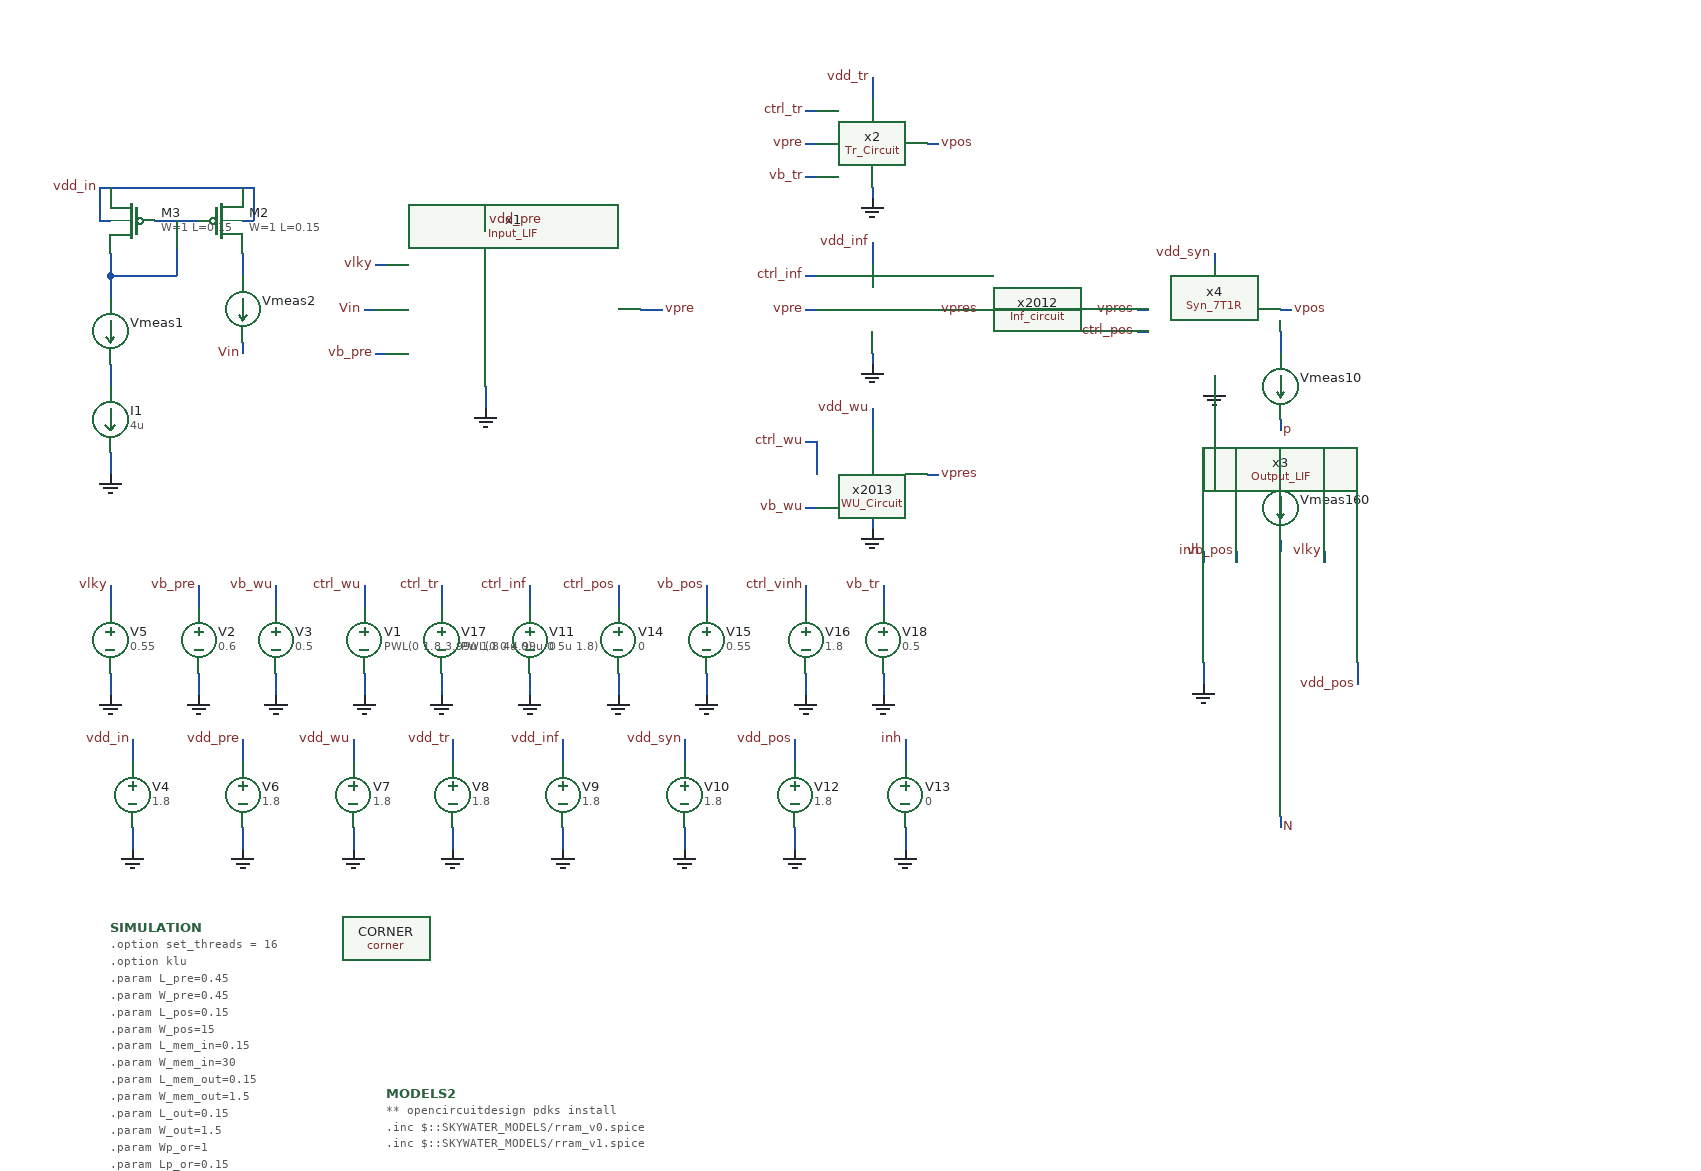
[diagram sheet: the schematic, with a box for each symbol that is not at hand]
v {xschem version=3.4.5 file_version=1.2
}
G {}
K {}
V {}
S {}
E {}
B 2 -1600 -1600 -800 -1200 {flags=graph
y1=-8e-07
y2=3.2e-06
ypos1=0
ypos2=2
divy=5
subdivy=1
unity=1
x1=0
x2=7e-05
divx=5
subdivx=1
xlabmag=1.0
ylabmag=1.0


dataset=-1
unitx=1
logx=0
logy=0



color=4
node=i(Vmeas1)}
B 2 -1600 -1200 -800 -800 {flags=graph
y1=0.34
y2=1.9
ypos1=0
ypos2=2
divy=5
subdivy=1
unity=1
x1=0
x2=7e-05
divx=5
subdivx=1
xlabmag=1.0
ylabmag=1.0


dataset=-1
unitx=1
logx=0
logy=0
color=4
node=vpre}
B 2 -800 -1200 0 -800 {flags=graph
y1=0
y2=1.8
ypos1=0
ypos2=2
divy=5
subdivy=1
unity=1
x1=0
x2=7e-05
divx=5
subdivx=1
xlabmag=1.0
ylabmag=1.0


dataset=-1
unitx=1
logx=0
logy=0



color=4
node=ctrl_wu}
B 2 -800 -1600 0 -1200 {flags=graph
y1=-4.1e-05
y2=0.00032
ypos1=0
ypos2=2
divy=5
subdivy=1
unity=1
x1=0
x2=7e-05
divx=5
subdivx=1
xlabmag=1.0
ylabmag=1.0


dataset=-1
unitx=1
logx=0
logy=0







color=17
node="\\"-1.8 i(v10) *\\""}
B 2 -1600 -800 -800 -400 {flags=graph
y1=1.1
y2=5.3
ypos1=0
ypos2=2
divy=5
subdivy=1
unity=1
x1=0
x2=7e-05
divx=5
subdivx=1
xlabmag=1.0
ylabmag=1.0


dataset=-1
unitx=1
logx=0
logy=0

color=6
node="\\"S20; 5 n.x4.xr1.n1#ngap -\\""}
B 2 -800 -800 0 -400 {flags=graph
y1=0
y2=1.8
ypos1=0
ypos2=2
divy=5
subdivy=1
unity=1
x1=0
x2=7e-05
divx=5
subdivx=1
xlabmag=1.0
ylabmag=1.0


dataset=-1
unitx=1
logx=0
logy=0



color="4 6 7"
node="ctrl_inf
ctrl_tr
ctrl_wu"}
B 2 -1600 -400 -800 0 {flags=graph
y1=0
y2=0.01
ypos1=0
ypos2=2
divy=5
subdivy=1
unity=1
x1=0
x2=7e-05
divx=5
subdivx=1
xlabmag=1.0
ylabmag=1.0


dataset=-1
unitx=1
logx=0
logy=0

color=6
node=\\"i(Vmeas10)\\"}
B 2 -800 -400 0 0 {flags=graph
y1=-0.42215
y2=1.75283
ypos1=0
ypos2=2
divy=5
subdivy=1
unity=1
x1=0
x2=7e-05
divx=5
subdivx=1
xlabmag=1.0
ylabmag=1.0


dataset=-1
unitx=1
logx=0
logy=0

color="6 4"
node="\\"p0\\"
\\"N0\\""}
N -2320 -1060 -2300 -1060 {
lab=vpre}
N -2720 -810 -2720 -790 {
lab=vb_pre}
N -2720 -730 -2720 -710 {
lab=GND}
N -2800 -930 -2800 -910 {
lab=GND}
N -2680 -1110 -2680 -1090 {
lab=#net1}
N -2680 -1140 -2670 -1140 {
lab=vdd_in}
N -2670 -1170 -2670 -1140 {
lab=vdd_in}
N -2680 -1170 -2670 -1170 {
lab=vdd_in}
N -2760 -1140 -2720 -1140 {
lab=#net2}
N -2800 -1170 -2680 -1170 {
lab=vdd_in}
N -2810 -1140 -2800 -1140 {
lab=vdd_in}
N -2810 -1170 -2810 -1140 {
lab=vdd_in}
N -2810 -1170 -2800 -1170 {
lab=vdd_in}
N -2800 -1110 -2800 -1090 {
lab=#net2}
N -2800 -1090 -2740 -1090 {
lab=#net2}
N -2740 -1140 -2740 -1090 {
lab=#net2}
N -2800 -1010 -2800 -990 {
lab=#net3}
N -2800 -1090 -2800 -1070 {
lab=#net2}
N -2780 -670 -2780 -650 {
lab=vdd_in}
N -2780 -590 -2780 -570 {
lab=GND}
N -2460 -990 -2460 -970 {
lab=GND}
N -2560 -1020 -2550 -1020 {
lab=vb_pre}
N -2680 -1030 -2680 -1020 {
lab=Vin}
N -2570 -1060 -2560 -1060 {
lab=Vin}
N -2560 -1100 -2550 -1100 {
lab=vlky}
N -2800 -810 -2800 -790 {
lab=vlky}
N -2800 -730 -2800 -710 {
lab=GND}
N -2460 -1140 -2460 -1130 {
lab=vdd_pre}
N -1800 -1000 -1800 -990 {
lab=GND}
N -1800 -1110 -1800 -1100 {
lab=vdd_syn}
N -1870 -1060 -1860 -1060 {
lab=vpres}
N -1740 -1060 -1730 -1060 {
lab=vpos}
N -2110 -870 -2110 -860 {
lab=GND}
N -2060 -910 -2050 -910 {
lab=vpres}
N -2110 -1020 -2110 -1010 {
lab=GND}
N -2060 -1060 -2050 -1060 {
lab=vpres}
N -2170 -880 -2160 -880 {
lab=vb_wu}
N -1740 -1040 -1740 -1020 {
lab=#net4}
N -1740 -960 -1740 -950 {
lab=p}
N -2170 -1090 -2160 -1090 {
lab=ctrl_inf}
N -2110 -970 -2110 -950 {
lab=vdd_wu}
N -2110 -1120 -2110 -1100 {
lab=vdd_inf}
N -2170 -940 -2160 -940 {
lab=ctrl_wu}
N -2160 -940 -2160 -910 {
lab=ctrl_wu}
N -2170 -1060 -2160 -1060 {
lab=vpre}
N -2680 -670 -2680 -650 {
lab=vdd_pre}
N -2680 -590 -2680 -570 {
lab=GND}
N -2580 -670 -2580 -650 {
lab=vdd_wu}
N -2580 -590 -2580 -570 {
lab=GND}
N -2490 -670 -2490 -650 {
lab=vdd_tr}
N -2490 -590 -2490 -570 {
lab=GND}
N -2390 -670 -2390 -650 {
lab=vdd_inf}
N -2390 -590 -2390 -570 {
lab=GND}
N -2280 -670 -2280 -650 {
lab=vdd_syn}
N -2280 -590 -2280 -570 {
lab=GND}
N -2570 -810 -2570 -790 {
lab=ctrl_wu}
N -2570 -730 -2570 -710 {
lab=GND}
N -2650 -810 -2650 -790 {
lab=vb_wu}
N -2650 -730 -2650 -710 {
lab=GND}
N -2420 -810 -2420 -790 {
lab=ctrl_inf}
N -2420 -730 -2420 -710 {
lab=GND}
N -1740 -850 -1740 -840 {
lab=#net5}
N -1740 -920 -1740 -910 {
lab=p1}
N -1740 -600 -1740 -590 {
lab=N}
N -1810 -740 -1810 -720 {
lab=GND}
N -1670 -740 -1670 -720 {
lab=vdd_pos}
N -1810 -840 -1810 -830 {
lab=inh}
N -1780 -840 -1780 -830 {
lab=vb_pos}
N -1700 -840 -1700 -830 {
lab=vlky}
N -2180 -670 -2180 -650 {
lab=vdd_pos}
N -2180 -590 -2180 -570 {
lab=GND}
N -2080 -670 -2080 -650 {
lab=inh}
N -2080 -590 -2080 -570 {
lab=GND}
N -2340 -810 -2340 -790 {
lab=ctrl_pos}
N -2340 -730 -2340 -710 {
lab=GND}
N -2260 -810 -2260 -790 {
lab=vb_pos}
N -2260 -730 -2260 -710 {
lab=GND}
N -2170 -810 -2170 -790 {
lab=ctrl_vinh}
N -2170 -730 -2170 -710 {
lab=GND}
N -2110 -1170 -2110 -1160 {
lab=GND}
N -2060 -1210 -2050 -1210 {
lab=vpos}
N -2170 -1180 -2160 -1180 {
lab=vb_tr}
N -2110 -1270 -2110 -1250 {
lab=vdd_tr}
N -2170 -1240 -2160 -1240 {
lab=ctrl_tr}
N -2170 -1210 -2160 -1210 {
lab=vpre}
N -2500 -810 -2500 -790 {
lab=ctrl_tr}
N -2500 -730 -2500 -710 {
lab=GND}
N -2100 -810 -2100 -790 {
lab=vb_tr}
N -2100 -730 -2100 -710 {
lab=GND}
N -1870 -1040 -1860 -1040 {
lab=ctrl_pos}
C {devices/gnd.sym} -2460 -970 0 0 {name=l1 lab=GND}
C {devices/lab_pin.sym} -2560 -1020 0 0 {name=p3 sig_type=std_logic lab=vb_pre}
C {devices/lab_pin.sym} -2300 -1060 2 0 {name=p5 sig_type=std_logic lab=vpre}
C {devices/vsource.sym} -2720 -760 0 0 {name=V2 value=0.6 savecurrent=false}
C {devices/lab_pin.sym} -2720 -810 0 0 {name=p6 sig_type=std_logic lab=vb_pre}
C {devices/gnd.sym} -2720 -710 0 0 {name=l4 lab=GND}
C {devices/code_shown.sym} -2800 -500 0 0 {name=SIMULATION
only_toplevel=true
value="
.option set_threads = 16
.option klu
.param L_pre=0.45
.param W_pre=0.45
.param L_pos=0.15
.param W_pos=15
.param L_mem_in=0.15
.param W_mem_in=30
.param L_mem_out=0.15
.param W_mem_out=1.5
.param L_out=0.15
.param W_out=1.5
.param Wp_or=1
.param Lp_or=0.15
.param Wn_or=1
.param Ln_or=0.15
.param Wp_or_inv=1
.param Lp_or_inv=0.15
.param Wn_or_inv=1
.param Ln_or_inv=0.15
.control
	set wr_vecnames
	set wr_singlescale
	let mc_runs = 150
	let run = 1
	dowhile run <= mc_runs
		tran 1n 70u 0
		*write Syn7T1R_MC\{$&run\}.raw
		wrdata Syn7T1R_MC\{$&run\}.txt v(n.x4.xr1.n1#ngap) i(v10)
		reset
		let run = run + 1
	end
.endc
.save all
" }
C {sky130_fd_pr/corner.sym} -2550 -490 0 0 {name=CORNER only_toplevel=true corner=tt_mm}
C {devices/isource.sym} -2800 -960 0 1 {name=I1 value=4u

}
C {devices/gnd.sym} -2800 -910 0 0 {name=l20 lab=GND}
C {sky130_fd_pr/pfet_01v8.sym} -2700 -1140 0 0 {name=M2
L=0.15
W=1
nf=1
mult=1
ad="'int((nf+1)/2) * W/nf * 0.29'" 
pd="'2*int((nf+1)/2) * (W/nf + 0.29)'"
as="'int((nf+2)/2) * W/nf * 0.29'" 
ps="'2*int((nf+2)/2) * (W/nf + 0.29)'"
nrd="'0.29 / W'" nrs="'0.29 / W'"
sa=0 sb=0 sd=0
model=pfet_01v8
spiceprefix=X
}
C {sky130_fd_pr/pfet_01v8.sym} -2780 -1140 0 1 {name=M3
L=0.15
W=1
nf=1
mult=1
ad="'int((nf+1)/2) * W/nf * 0.29'" 
pd="'2*int((nf+1)/2) * (W/nf + 0.29)'"
as="'int((nf+2)/2) * W/nf * 0.29'" 
ps="'2*int((nf+2)/2) * (W/nf + 0.29)'"
nrd="'0.29 / W'" nrs="'0.29 / W'"
sa=0 sb=0 sd=0
model=pfet_01v8
spiceprefix=X
}
C {devices/lab_pin.sym} -2680 -1020 0 0 {name=p10 sig_type=std_logic lab=Vin}
C {devices/ammeter.sym} -2800 -1040 0 0 {name=Vmeas1 savecurrent=true}
C {devices/ammeter.sym} -2680 -1060 0 0 {name=Vmeas2 savecurrent=true}
C {devices/vsource.sym} -2780 -620 0 0 {name=V4 savecurrent=false value=1.8
*"PWL(0 0 39.9u 0 40u 1.8)"}
C {devices/lab_pin.sym} -2780 -670 0 0 {name=p1 sig_type=std_logic lab=vdd_in}
C {devices/gnd.sym} -2780 -570 0 0 {name=l6 lab=GND}
C {devices/lab_pin.sym} -2570 -1060 0 0 {name=p8 sig_type=std_logic lab=Vin}
C {devices/lab_pin.sym} -2560 -1100 0 0 {name=p11 sig_type=std_logic lab=vlky}
C {devices/vsource.sym} -2800 -760 0 0 {name=V5 savecurrent=false value=0.55}
C {devices/lab_pin.sym} -2800 -810 0 0 {name=p13 sig_type=std_logic lab=vlky}
C {devices/gnd.sym} -2800 -710 0 0 {name=l9 lab=GND}
C {devices/launcher.sym} -1680 -1240 0 0 {name=h5
descr="load waves" 
tclcommand="xschem raw_read $netlist_dir/Syn7T1R_MC2.raw tran"
}
C {/home/ricardo/RATT_repos/Proyectos_xschem/SNN/Input_LIF.sym} -2460 -1060 0 0 {name=x1}
C {devices/lab_pin.sym} -2050 -1210 2 0 {name=p162 sig_type=std_logic lab=vpos}
C {devices/gnd.sym} -1800 -990 0 0 {name=l39 lab=GND}
C {devices/lab_pin.sym} -1870 -1060 0 0 {name=p26 sig_type=std_logic lab=vpres}
C {devices/ammeter.sym} -1740 -990 0 0 {name=Vmeas10 savecurrent=true}
C {devices/lab_pin.sym} -1740 -950 2 0 {name=p46 sig_type=std_logic lab=p}
C {devices/lab_pin.sym} -2050 -910 2 0 {name=p35 sig_type=std_logic lab=vpres}
C {devices/gnd.sym} -2110 -860 0 0 {name=l18 lab=GND}
C {devices/lab_pin.sym} -2170 -1060 0 0 {name=p41 sig_type=std_logic lab=vpre}
C {devices/lab_pin.sym} -2170 -1090 0 0 {name=p42 sig_type=std_logic lab=ctrl_inf}
C {devices/gnd.sym} -2110 -1010 0 0 {name=l10 lab=GND}
C {devices/lab_pin.sym} -2110 -970 0 0 {name=p47 sig_type=std_logic lab=vdd_wu}
C {devices/lab_pin.sym} -2110 -1120 0 0 {name=p48 sig_type=std_logic lab=vdd_inf}
C {devices/lab_pin.sym} -1800 -1110 0 0 {name=p63 sig_type=std_logic lab=vdd_syn}
C {/home/ricardo/RATT_repos/Proyectos_xschem/SNN/Inf_circuit.sym} -2110 -1060 0 0 {name=x2012}
C {/home/ricardo/RATT_repos/Proyectos_xschem/SNN/WU_Circuit.sym} -2110 -910 0 0 {name=x2013}
C {devices/lab_pin.sym} -2170 -940 0 0 {name=p36 sig_type=std_logic lab=ctrl_wu}
C {devices/lab_pin.sym} -2170 -880 0 0 {name=p283 sig_type=std_logic lab=vb_wu}
C {devices/lab_pin.sym} -1730 -1060 2 0 {name=p405 sig_type=std_logic lab=vpos}
C {devices/vsource.sym} -2680 -620 0 0 {name=V6 savecurrent=false value=1.8
*"PWL(0 0 39.9u 0 40u 1.8)"}
C {devices/lab_pin.sym} -2680 -670 0 0 {name=p2 sig_type=std_logic lab=vdd_pre}
C {devices/gnd.sym} -2680 -570 0 0 {name=l11 lab=GND}
C {devices/vsource.sym} -2580 -620 0 0 {name=V7 
value=1.8}
C {devices/gnd.sym} -2580 -570 0 0 {name=l3 lab=GND}
C {devices/lab_pin.sym} -2810 -1170 0 0 {name=p4 sig_type=std_logic lab=vdd_in}
C {devices/lab_pin.sym} -2580 -670 0 0 {name=p9 sig_type=std_logic lab=vdd_wu}
C {devices/vsource.sym} -2490 -620 0 0 {name=V8 
value=1.8}
C {devices/gnd.sym} -2490 -570 0 0 {name=l7 lab=GND}
C {devices/lab_pin.sym} -2490 -670 0 0 {name=p12 sig_type=std_logic lab=vdd_tr}
C {devices/vsource.sym} -2390 -620 0 0 {name=V9 
value=1.8}
C {devices/gnd.sym} -2390 -570 0 0 {name=l12 lab=GND}
C {devices/lab_pin.sym} -2390 -670 0 0 {name=p14 sig_type=std_logic lab=vdd_inf}
C {devices/vsource.sym} -2280 -620 0 0 {name=V10 
value=1.8}
C {devices/gnd.sym} -2280 -570 0 0 {name=l14 lab=GND}
C {devices/lab_pin.sym} -2280 -670 0 0 {name=p15 sig_type=std_logic lab=vdd_syn}
C {devices/lab_pin.sym} -2460 -1140 2 0 {name=p7 sig_type=std_logic lab=vdd_pre}
C {devices/vsource.sym} -2570 -760 0 0 {name=V1 savecurrent=false value="PWL(0 1.8 3.99u 1.8 4u 0)"}
C {devices/lab_pin.sym} -2570 -810 0 0 {name=p16 sig_type=std_logic lab=ctrl_wu}
C {devices/gnd.sym} -2570 -710 0 0 {name=l2 lab=GND}
C {devices/vsource.sym} -2650 -760 0 0 {name=V3 savecurrent=false value=0.5}
C {devices/lab_pin.sym} -2650 -810 0 0 {name=p17 sig_type=std_logic lab=vb_wu}
C {devices/gnd.sym} -2650 -710 0 0 {name=l5 lab=GND}
C {devices/vsource.sym} -2420 -760 0 0 {name=V11 savecurrent=false value=0
*"PWL(0 0 84.9u 0 85u 1.8)"}
C {devices/lab_pin.sym} -2420 -810 0 0 {name=p18 sig_type=std_logic lab=ctrl_inf}
C {devices/gnd.sym} -2420 -710 0 0 {name=l15 lab=GND}
C {devices/lab_pin.sym} -1780 -840 1 0 {name=p19 sig_type=std_logic lab=vb_pos}
C {devices/gnd.sym} -1810 -720 0 0 {name=l16 lab=GND}
C {devices/ammeter.sym} -1740 -880 0 0 {name=Vmeas160 savecurrent=true}
C {devices/lab_pin.sym} -1740 -920 2 0 {name=p20 sig_type=std_logic lab=p1}
C {devices/lab_pin.sym} -1740 -590 2 0 {name=p21 sig_type=std_logic lab=N}
C {devices/lab_pin.sym} -1670 -720 3 0 {name=p22 sig_type=std_logic lab=vdd_pos}
C {devices/lab_pin.sym} -1810 -840 1 0 {name=p23 sig_type=std_logic lab=inh}
C {devices/lab_pin.sym} -1700 -840 1 0 {name=p24 sig_type=std_logic lab=vlky}
C {devices/vsource.sym} -2180 -620 0 0 {name=V12 
value=1.8}
C {devices/gnd.sym} -2180 -570 0 0 {name=l17 lab=GND}
C {devices/lab_pin.sym} -2180 -670 0 0 {name=p27 sig_type=std_logic lab=vdd_pos}
C {devices/vsource.sym} -2080 -620 0 0 {name=V13 
value=0}
C {devices/gnd.sym} -2080 -570 0 0 {name=l19 lab=GND}
C {devices/lab_pin.sym} -2080 -670 0 0 {name=p28 sig_type=std_logic lab=inh}
C {devices/vsource.sym} -2340 -760 0 0 {name=V14 savecurrent=false value=0
*"PWL(0 0 84.9u 0 85u 1.8)"}
C {devices/lab_pin.sym} -2340 -810 0 0 {name=p29 sig_type=std_logic lab=ctrl_pos}
C {devices/gnd.sym} -2340 -710 0 0 {name=l23 lab=GND}
C {devices/vsource.sym} -2260 -760 0 0 {name=V15 savecurrent=false value=0.55}
C {devices/lab_pin.sym} -2260 -810 0 0 {name=p30 sig_type=std_logic lab=vb_pos}
C {devices/gnd.sym} -2260 -710 0 0 {name=l24 lab=GND}
C {devices/vsource.sym} -2170 -760 0 0 {name=V16 savecurrent=false value=1.8}
C {devices/lab_pin.sym} -2170 -810 0 0 {name=p33 sig_type=std_logic lab=ctrl_vinh}
C {devices/gnd.sym} -2170 -710 0 0 {name=l25 lab=GND}
C {devices/code.sym} -2550 -350 0 0 {name=MODELS2
only_toplevel=true
format="tcleval( @value )"
value="
** opencircuitdesign pdks install
.inc $::SKYWATER_MODELS/rram_v0.spice
.inc $::SKYWATER_MODELS/rram_v1.spice
"
spice_ignore=false}
C {/home/ricardo/RATT_repos/Proyectos_xschem/SNN/Tr_Circuit.sym} -2110 -1210 0 0 {name=x2}
C {devices/lab_pin.sym} -2050 -1060 2 0 {name=p34 sig_type=std_logic lab=vpres}
C {devices/gnd.sym} -2110 -1160 0 0 {name=l13 lab=GND}
C {devices/lab_pin.sym} -2110 -1270 0 0 {name=p37 sig_type=std_logic lab=vdd_tr}
C {devices/lab_pin.sym} -2170 -1240 0 0 {name=p38 sig_type=std_logic lab=ctrl_tr}
C {devices/lab_pin.sym} -2170 -1180 0 0 {name=p39 sig_type=std_logic lab=vb_tr}
C {devices/vsource.sym} -2500 -760 0 0 {name=V17 savecurrent=false value="PWL(0 0 4.99u 0 5u 1.8)"}
C {devices/lab_pin.sym} -2500 -810 0 0 {name=p43 sig_type=std_logic lab=ctrl_tr}
C {devices/gnd.sym} -2500 -710 0 0 {name=l26 lab=GND}
C {devices/vsource.sym} -2100 -760 0 0 {name=V18 savecurrent=false value=0.5}
C {devices/lab_pin.sym} -2100 -810 0 0 {name=p44 sig_type=std_logic lab=vb_tr}
C {devices/gnd.sym} -2100 -710 0 0 {name=l28 lab=GND}
C {devices/lab_pin.sym} -2170 -1210 0 0 {name=p40 sig_type=std_logic lab=vpre}
C {/home/ricardo/RATT_repos/Proyectos_xschem/SNN/Output_LIF.sym} -1740 -740 1 0 {name=x3}
C {/home/ricardo/RATT_repos/Proyectos_xschem/SNN/Syn_7T1R.sym} -1510 -920 0 0 {name=x4}
C {devices/lab_pin.sym} -1870 -1040 0 0 {name=p25 sig_type=std_logic lab=ctrl_pos}
